VERSION 5.7 ;
BUSBITCHARS "[]" ;
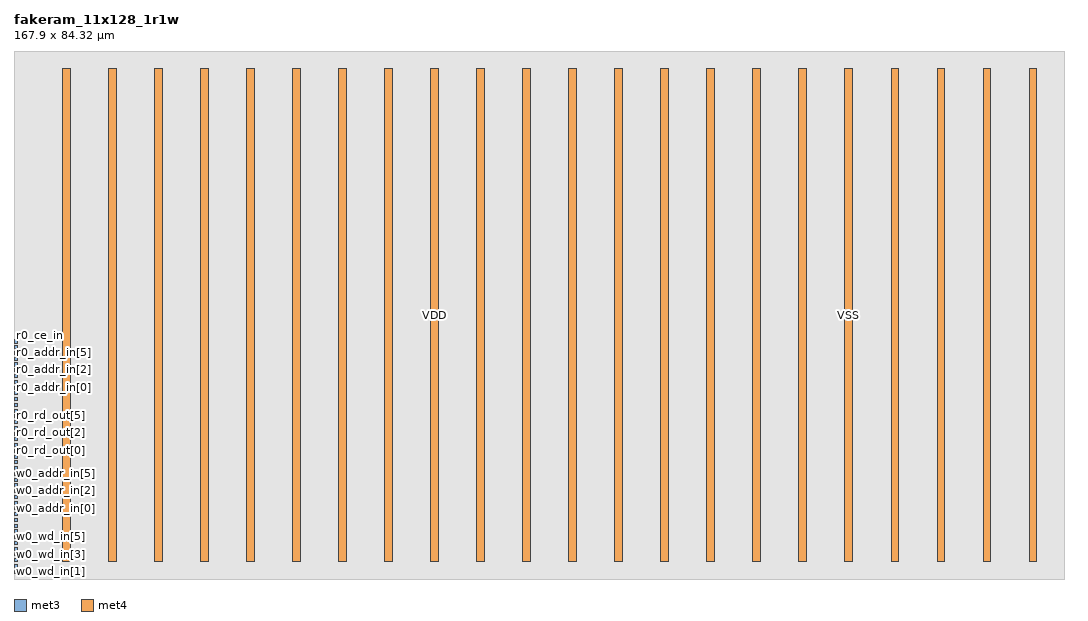
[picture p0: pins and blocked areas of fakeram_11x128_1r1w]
MACRO fakeram_11x128_1r1w
  FOREIGN fakeram_11x128_1r1w 0 0 ;
  SYMMETRY X Y R90 ;
  SIZE 167.900 BY 84.320 ;
  CLASS BLOCK ;
  PIN w0_wd_in[0]
    DIRECTION INPUT ;
    USE SIGNAL ;
    SHAPE ABUTMENT ;
    PORT
      LAYER met3 ;
      RECT 0.000 0.920 0.500 1.420 ;
    END
  END w0_wd_in[0]
  PIN w0_wd_in[1]
    DIRECTION INPUT ;
    USE SIGNAL ;
    SHAPE ABUTMENT ;
    PORT
      LAYER met3 ;
      RECT 0.000 1.840 0.500 2.340 ;
    END
  END w0_wd_in[1]
  PIN w0_wd_in[2]
    DIRECTION INPUT ;
    USE SIGNAL ;
    SHAPE ABUTMENT ;
    PORT
      LAYER met3 ;
      RECT 0.000 2.760 0.500 3.260 ;
    END
  END w0_wd_in[2]
  PIN w0_wd_in[3]
    DIRECTION INPUT ;
    USE SIGNAL ;
    SHAPE ABUTMENT ;
    PORT
      LAYER met3 ;
      RECT 0.000 3.680 0.500 4.180 ;
    END
  END w0_wd_in[3]
  PIN w0_wd_in[4]
    DIRECTION INPUT ;
    USE SIGNAL ;
    SHAPE ABUTMENT ;
    PORT
      LAYER met3 ;
      RECT 0.000 4.600 0.500 5.100 ;
    END
  END w0_wd_in[4]
  PIN w0_wd_in[5]
    DIRECTION INPUT ;
    USE SIGNAL ;
    SHAPE ABUTMENT ;
    PORT
      LAYER met3 ;
      RECT 0.000 5.520 0.500 6.020 ;
    END
  END w0_wd_in[5]
  PIN w0_wd_in[6]
    DIRECTION INPUT ;
    USE SIGNAL ;
    SHAPE ABUTMENT ;
    PORT
      LAYER met3 ;
      RECT 0.000 6.440 0.500 6.940 ;
    END
  END w0_wd_in[6]
  PIN w0_wd_in[7]
    DIRECTION INPUT ;
    USE SIGNAL ;
    SHAPE ABUTMENT ;
    PORT
      LAYER met3 ;
      RECT 0.000 7.360 0.500 7.860 ;
    END
  END w0_wd_in[7]
  PIN w0_wd_in[8]
    DIRECTION INPUT ;
    USE SIGNAL ;
    SHAPE ABUTMENT ;
    PORT
      LAYER met3 ;
      RECT 0.000 8.280 0.500 8.780 ;
    END
  END w0_wd_in[8]
  PIN w0_wd_in[9]
    DIRECTION INPUT ;
    USE SIGNAL ;
    SHAPE ABUTMENT ;
    PORT
      LAYER met3 ;
      RECT 0.000 9.200 0.500 9.700 ;
    END
  END w0_wd_in[9]
  PIN w0_wd_in[10]
    DIRECTION INPUT ;
    USE SIGNAL ;
    SHAPE ABUTMENT ;
    PORT
      LAYER met3 ;
      RECT 0.000 10.120 0.500 10.620 ;
    END
  END w0_wd_in[10]
  PIN w0_addr_in[0]
    DIRECTION INPUT ;
    USE SIGNAL ;
    SHAPE ABUTMENT ;
    PORT
      LAYER met3 ;
      RECT 0.000 11.040 0.500 11.540 ;
    END
  END w0_addr_in[0]
  PIN w0_addr_in[1]
    DIRECTION INPUT ;
    USE SIGNAL ;
    SHAPE ABUTMENT ;
    PORT
      LAYER met3 ;
      RECT 0.000 11.960 0.500 12.460 ;
    END
  END w0_addr_in[1]
  PIN w0_addr_in[2]
    DIRECTION INPUT ;
    USE SIGNAL ;
    SHAPE ABUTMENT ;
    PORT
      LAYER met3 ;
      RECT 0.000 12.880 0.500 13.380 ;
    END
  END w0_addr_in[2]
  PIN w0_addr_in[3]
    DIRECTION INPUT ;
    USE SIGNAL ;
    SHAPE ABUTMENT ;
    PORT
      LAYER met3 ;
      RECT 0.000 13.800 0.500 14.300 ;
    END
  END w0_addr_in[3]
  PIN w0_addr_in[4]
    DIRECTION INPUT ;
    USE SIGNAL ;
    SHAPE ABUTMENT ;
    PORT
      LAYER met3 ;
      RECT 0.000 14.720 0.500 15.220 ;
    END
  END w0_addr_in[4]
  PIN w0_addr_in[5]
    DIRECTION INPUT ;
    USE SIGNAL ;
    SHAPE ABUTMENT ;
    PORT
      LAYER met3 ;
      RECT 0.000 15.640 0.500 16.140 ;
    END
  END w0_addr_in[5]
  PIN w0_addr_in[6]
    DIRECTION INPUT ;
    USE SIGNAL ;
    SHAPE ABUTMENT ;
    PORT
      LAYER met3 ;
      RECT 0.000 16.560 0.500 17.060 ;
    END
  END w0_addr_in[6]
  PIN w0_clk
    DIRECTION INPUT ;
    USE SIGNAL ;
    SHAPE ABUTMENT ;
    PORT
      LAYER met3 ;
      RECT 0.000 17.480 0.500 17.980 ;
    END
  END w0_clk
  PIN w0_ce_in
    DIRECTION INPUT ;
    USE SIGNAL ;
    SHAPE ABUTMENT ;
    PORT
      LAYER met3 ;
      RECT 0.000 18.400 0.500 18.900 ;
    END
  END w0_ce_in
  PIN w0_we_in
    DIRECTION INPUT ;
    USE SIGNAL ;
    SHAPE ABUTMENT ;
    PORT
      LAYER met3 ;
      RECT 0.000 19.320 0.500 19.820 ;
    END
  END w0_we_in
  PIN r0_rd_out[0]
    DIRECTION OUTPUT ;
    USE SIGNAL ;
    SHAPE ABUTMENT ;
    PORT
      LAYER met3 ;
      RECT 0.000 20.240 0.500 20.740 ;
    END
  END r0_rd_out[0]
  PIN r0_rd_out[1]
    DIRECTION OUTPUT ;
    USE SIGNAL ;
    SHAPE ABUTMENT ;
    PORT
      LAYER met3 ;
      RECT 0.000 21.160 0.500 21.660 ;
    END
  END r0_rd_out[1]
  PIN r0_rd_out[2]
    DIRECTION OUTPUT ;
    USE SIGNAL ;
    SHAPE ABUTMENT ;
    PORT
      LAYER met3 ;
      RECT 0.000 22.080 0.500 22.580 ;
    END
  END r0_rd_out[2]
  PIN r0_rd_out[3]
    DIRECTION OUTPUT ;
    USE SIGNAL ;
    SHAPE ABUTMENT ;
    PORT
      LAYER met3 ;
      RECT 0.000 23.000 0.500 23.500 ;
    END
  END r0_rd_out[3]
  PIN r0_rd_out[4]
    DIRECTION OUTPUT ;
    USE SIGNAL ;
    SHAPE ABUTMENT ;
    PORT
      LAYER met3 ;
      RECT 0.000 23.920 0.500 24.420 ;
    END
  END r0_rd_out[4]
  PIN r0_rd_out[5]
    DIRECTION OUTPUT ;
    USE SIGNAL ;
    SHAPE ABUTMENT ;
    PORT
      LAYER met3 ;
      RECT 0.000 24.840 0.500 25.340 ;
    END
  END r0_rd_out[5]
  PIN r0_rd_out[6]
    DIRECTION OUTPUT ;
    USE SIGNAL ;
    SHAPE ABUTMENT ;
    PORT
      LAYER met3 ;
      RECT 0.000 25.760 0.500 26.260 ;
    END
  END r0_rd_out[6]
  PIN r0_rd_out[7]
    DIRECTION OUTPUT ;
    USE SIGNAL ;
    SHAPE ABUTMENT ;
    PORT
      LAYER met3 ;
      RECT 0.000 26.680 0.500 27.180 ;
    END
  END r0_rd_out[7]
  PIN r0_rd_out[8]
    DIRECTION OUTPUT ;
    USE SIGNAL ;
    SHAPE ABUTMENT ;
    PORT
      LAYER met3 ;
      RECT 0.000 27.600 0.500 28.100 ;
    END
  END r0_rd_out[8]
  PIN r0_rd_out[9]
    DIRECTION OUTPUT ;
    USE SIGNAL ;
    SHAPE ABUTMENT ;
    PORT
      LAYER met3 ;
      RECT 0.000 28.520 0.500 29.020 ;
    END
  END r0_rd_out[9]
  PIN r0_rd_out[10]
    DIRECTION OUTPUT ;
    USE SIGNAL ;
    SHAPE ABUTMENT ;
    PORT
      LAYER met3 ;
      RECT 0.000 29.440 0.500 29.940 ;
    END
  END r0_rd_out[10]
  PIN r0_addr_in[0]
    DIRECTION INPUT ;
    USE SIGNAL ;
    SHAPE ABUTMENT ;
    PORT
      LAYER met3 ;
      RECT 0.000 30.360 0.500 30.860 ;
    END
  END r0_addr_in[0]
  PIN r0_addr_in[1]
    DIRECTION INPUT ;
    USE SIGNAL ;
    SHAPE ABUTMENT ;
    PORT
      LAYER met3 ;
      RECT 0.000 31.280 0.500 31.780 ;
    END
  END r0_addr_in[1]
  PIN r0_addr_in[2]
    DIRECTION INPUT ;
    USE SIGNAL ;
    SHAPE ABUTMENT ;
    PORT
      LAYER met3 ;
      RECT 0.000 32.200 0.500 32.700 ;
    END
  END r0_addr_in[2]
  PIN r0_addr_in[3]
    DIRECTION INPUT ;
    USE SIGNAL ;
    SHAPE ABUTMENT ;
    PORT
      LAYER met3 ;
      RECT 0.000 33.120 0.500 33.620 ;
    END
  END r0_addr_in[3]
  PIN r0_addr_in[4]
    DIRECTION INPUT ;
    USE SIGNAL ;
    SHAPE ABUTMENT ;
    PORT
      LAYER met3 ;
      RECT 0.000 34.040 0.500 34.540 ;
    END
  END r0_addr_in[4]
  PIN r0_addr_in[5]
    DIRECTION INPUT ;
    USE SIGNAL ;
    SHAPE ABUTMENT ;
    PORT
      LAYER met3 ;
      RECT 0.000 34.960 0.500 35.460 ;
    END
  END r0_addr_in[5]
  PIN r0_addr_in[6]
    DIRECTION INPUT ;
    USE SIGNAL ;
    SHAPE ABUTMENT ;
    PORT
      LAYER met3 ;
      RECT 0.000 35.880 0.500 36.380 ;
    END
  END r0_addr_in[6]
  PIN r0_clk
    DIRECTION INPUT ;
    USE SIGNAL ;
    SHAPE ABUTMENT ;
    PORT
      LAYER met3 ;
      RECT 0.000 36.800 0.500 37.300 ;
    END
  END r0_clk
  PIN r0_ce_in
    DIRECTION INPUT ;
    USE SIGNAL ;
    SHAPE ABUTMENT ;
    PORT
      LAYER met3 ;
      RECT 0.000 37.720 0.500 38.220 ;
    END
  END r0_ce_in
  PIN VDD
    DIRECTION INOUT ;
    USE POWER ;
    PORT
      LAYER met4 ;
      RECT 7.760 2.720 8.960 81.600 ;
      RECT 22.480 2.720 23.680 81.600 ;
      RECT 37.200 2.720 38.400 81.600 ;
      RECT 51.920 2.720 53.120 81.600 ;
      RECT 66.640 2.720 67.840 81.600 ;
      RECT 81.360 2.720 82.560 81.600 ;
      RECT 96.080 2.720 97.280 81.600 ;
      RECT 110.800 2.720 112.000 81.600 ;
      RECT 125.520 2.720 126.720 81.600 ;
      RECT 140.240 2.720 141.440 81.600 ;
      RECT 154.960 2.720 156.160 81.600 ;
    END
  END VDD
  PIN VSS
    DIRECTION INOUT ;
    USE GROUND ;
    PORT
      LAYER met4 ;
      RECT 15.120 2.720 16.320 81.600 ;
      RECT 29.840 2.720 31.040 81.600 ;
      RECT 44.560 2.720 45.760 81.600 ;
      RECT 59.280 2.720 60.480 81.600 ;
      RECT 74.000 2.720 75.200 81.600 ;
      RECT 88.720 2.720 89.920 81.600 ;
      RECT 103.440 2.720 104.640 81.600 ;
      RECT 118.160 2.720 119.360 81.600 ;
      RECT 132.880 2.720 134.080 81.600 ;
      RECT 147.600 2.720 148.800 81.600 ;
      RECT 162.320 2.720 163.520 81.600 ;
    END
  END VSS
  OBS
    LAYER met1 ;
      RECT 0.000 0.000 167.900 84.320 ;
    LAYER met2 ;
      RECT 0.000 0.000 167.900 84.320 ;
    LAYER met3 ;
      RECT 0.000 0.000 167.900 84.320 ;
  END
END fakeram_11x128_1r1w
END LIBRARY
